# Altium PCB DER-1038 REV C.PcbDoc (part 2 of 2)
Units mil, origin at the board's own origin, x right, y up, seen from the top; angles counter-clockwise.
Board outline 9818.9 x 992.13 mil, 2 copper layers (TOP, BOTTOM), stack 10.4 mil thick; 94 components, 52 nets, 258 pads, 996 vias.

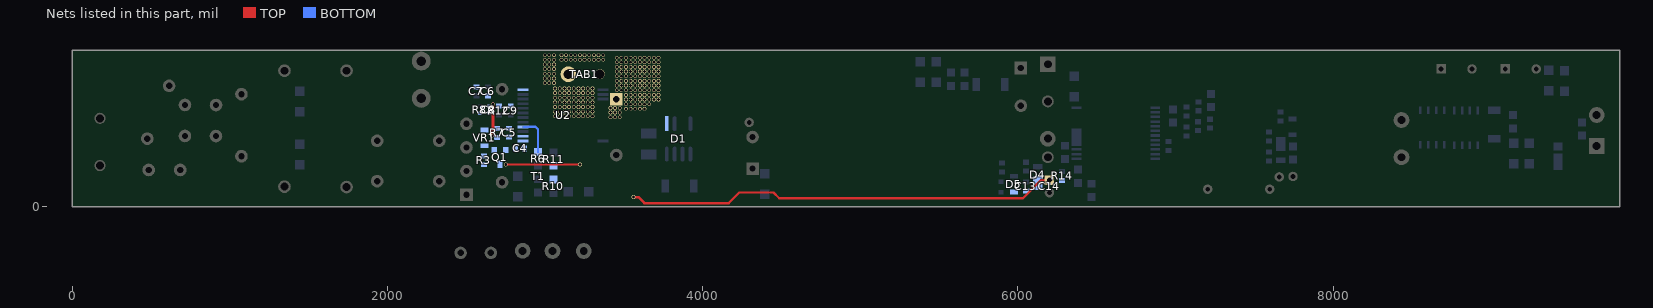
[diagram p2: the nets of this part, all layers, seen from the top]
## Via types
v1: diameter 24, hole 18, TOP to BOTTOM, 995 vias
v2: diameter 60, hole 35, TOP to BOTTOM, 1 vias

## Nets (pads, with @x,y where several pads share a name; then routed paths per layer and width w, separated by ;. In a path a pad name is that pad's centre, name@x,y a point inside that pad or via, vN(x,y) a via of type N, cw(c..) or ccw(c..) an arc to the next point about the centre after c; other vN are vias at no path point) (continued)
N13967788: C5.1 R6.2 R7.1 U2.4 | length 247.7
  BOTTOM w15: U2.4@2860.26,506.18 2892.32,506.18 2893.5,507.36 2902.79,507.36 2903.59,508.15 2937.85,508.15 2955,491 R6.2@2955,346
N13967796: R10.2 R11.2
N13967854: C4.1 Q1.2 U2.1
N13967858: C4.2 C5.2 C6.2 C7.2 C8.2 C9.2 R7.2 R12.1 U2.2 U2.12 VR1.2 | length 205.7
  TOP w20: v1(2661,448) 2661,477 2670,486 v1(2670,650)
N13968000: C8.1 R8.2
N13968020: Q1.1 R3.2 VR1.1
N13971397: D1.1 T1.1 TAB1.1 TAB1.2 U2.16
  other v1: 3414.28,567.95 3443.81,567.95 3473.34,567.95 3063.23,573.58 3093.23,573.58 3122.76,573.58 3152.28,573.58 3181.81,573.58 3211.34,573.58 3240.87,573.58 3270.39,573.58 3299.92,573.58 3414.28,597.47 3443.81,597.47 3473.34,597.47 3063.23,603.11 3093.23,603.11 3122.76,603.11 3152.28,603.11 3181.81,603.11 3211.34,603.11 3240.87,603.11 3270.39,603.11 3299.92,603.11 3513.28,620.95 3542.81,620.95 3572.34,620.95 3601.87,620.95 3631.39,620.95 3414.28,627 3443.81,627 3473.34,627 3063.23,632.64 3093.23,632.64 3122.76,632.64 3152.28,632.64 3181.81,632.64 3211.34,632.64 3240.87,632.64 3270.39,632.64 3299.92,632.64 3513.28,650.47 3542.81,650.47 3572.34,650.47 3601.87,650.47 3631.39,650.47 3660.92,650.47 3063.23,662.16 3093.23,662.16 3122.76,662.16 3152.28,662.16 3181.81,662.16 3211.34,662.16 3240.87,662.16 3270.39,662.16 3299.92,662.16 3513.28,680 3542.81,680 3572.34,680 3601.87,680 3631.39,680 3660.92,680 3690.45,680 3719.98,680 3063.23,691.69 3093.23,691.69 3122.76,691.69 3152.28,691.69 3181.81,691.69 3211.34,691.69 3240.87,691.69 3270.39,691.69 3299.92,691.69 3513.28,709.53 3542.81,709.53 3572.34,709.53 3601.87,709.53 3631.39,709.53 3660.92,709.53 3690.45,709.53 3719.98,709.53 3063.23,721.22 3093.23,721.22 3122.76,721.22 3152.28,721.22 3181.81,721.22 3211.34,721.22 3240.87,721.22 3270.39,721.22 3299.92,721.22 3454.23,739.05 3483.76,739.05 3513.28,739.05 3542.81,739.05 3572.34,739.05 3601.87,739.05 3631.39,739.05 3660.92,739.05 3690.45,739.05 3719.98,739.05 3063.23,750.75 3093.23,750.75 3122.76,750.75 3152.28,750.75 3181.81,750.75 3211.34,750.75 3240.87,750.75 3270.39,750.75 3299.92,750.75 3454.23,768.58 3483.76,768.58 3513.28,768.58 3542.81,768.58 3572.34,768.58 3601.87,768.58 3631.39,768.58 3660.92,768.58 3690.45,768.58 3719.98,768.58 2997.23,784.58 3026.76,784.58 3056.28,784.58 3454.23,798.11 3483.76,798.11 3513.28,798.11 3542.81,798.11 3572.34,798.11 3601.87,798.11 3631.39,798.11 3660.92,798.11 3690.45,798.11 3719.98,798.11 2997.23,814.11 3026.76,814.11 3056.28,814.11 3454.23,827.64 3483.76,827.64 3513.28,827.64 3542.81,827.64 3572.34,827.64 3601.87,827.64 3631.39,827.64 3660.92,827.64 3690.45,827.64 3719.98,827.64 2997.23,843.64 3026.76,843.64 3056.28,843.64 3454.23,857.16 3483.76,857.16 3513.28,857.16 3542.81,857.16 3572.34,857.16 3601.87,857.16 3631.39,857.16 3660.92,857.16 3690.45,857.16 3719.98,857.16 2997.23,873.16 3026.76,873.16 3056.28,873.16 3454.23,886.69 3483.76,886.69 3513.28,886.69 3542.81,886.69 3572.34,886.69 3601.87,886.69 3631.39,886.69 3660.92,886.69 3690.45,886.69 3719.98,886.69 2997.23,902.69 3026.76,902.69 3056.28,902.69 3454.23,916.22 3483.76,916.22 3513.28,916.22 3542.81,916.22 3572.34,916.22 3601.87,916.22 3631.39,916.22 3660.92,916.22 3690.45,916.22 3719.98,916.22 2997.23,932.22 3026.76,932.22 3056.28,932.22 3103.23,932.22 3132.76,932.22 3162.28,932.22 3191.81,932.22 3221.34,932.22 3250.87,932.22 3280.39,932.22 3309.92,932.22 3339.45,932.22 3368.98,932.22 3454.23,945.75 3483.76,945.75 3513.28,945.75 3542.81,945.75 3572.34,945.75 3601.87,945.75 3631.39,945.75 3660.92,945.75 3690.45,945.75 3719.98,945.75 2997.23,961.75 3026.76,961.75 3056.28,961.75 3103.23,961.75 3132.76,961.75 3162.28,961.75 3191.81,961.75 3221.34,961.75 3250.87,961.75 3280.39,961.75 3309.92,961.75 3339.45,961.75 3368.98,961.75
VCCP: C13.1 C14.1 D4.1 D5.2 Q1.3 R3.1 R14.1 | length 3216.4
  TOP w15: v1(2750,268) v1(3221,268) ; v1(3561,61) 3592,61 3630,23 4165,23 4232,90 4450,90 4486,54 6032,54 6147,169 C14.1@6200.37,169
pads on no net: D1. PI_SPARK_GAP_6P4MM.1 PI_SPARK_GAP_6P4MM.2 T1.2 T1.3 T2.2 T2.4 T2.8 U1.6 U2.7 U2.9 U2.10 U2.11 U2.13 U2.14 U2.15 U3.8 U3.9 U3.10 U3.11 U3.12

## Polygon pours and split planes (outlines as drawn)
N13421894 on BOTTOM "BOTTOM-N13421894" (solid, remove dead copper, pour order 10): 19 vertices, not listed, extent 6937,341 7032.5,406
N13967702 on BOTTOM "BOTTOM-N13967702" (solid, remove dead copper, pour order 44): 3033,120 3103,120 3111,128 3174,128 3177,125 3177,59 3047,59 3031,59 3030,60 3030,67 3028,69 3028,115
N13420648 on BOTTOM "BOTTOM-N13420648" (solid, remove dead copper, pour order 59): 22 vertices, not listed, extent 3335,386 3707,497
N13420648 on BOTTOM "BOTTOM-N13420648 1" (solid, remove dead copper, pour order 39): 2440,564 2515,564 2539,540 2539,495 2530,486 2458,486 2429,515 2429,553
N13967734 on BOTTOM "BOTTOM-N13967734" (solid, remove dead copper, pour order 5): 2618,745 2618,794 2624,800 2648,800 2656,792 2656,745
N13515268 on BOTTOM "BOTTOM-N13515268" (solid, remove dead copper, pour order 11): 6037,237 6037,146 6041,142 6068,142 6072,146 6072,235 6067,240 6040,240
N13473411 on BOTTOM "BOTTOM-N13473411" (solid, remove dead copper, pour order 14): 5877,234 5877,149 5880,146 5910,146 5918,154 5918,230 5911,237 5880,237
N13967764 on BOTTOM "BOTTOM-N13967764" (solid, remove dead copper, pour order 0): 2804,544 2888,544 2890,542 2890,528 2889,527 2805,527 2799,533 2799,539
N13968020 on BOTTOM "BOTTOM-N13968020" (solid, remove dead copper, pour order 43): 2586,400 2586,313 2592,307 2659,307 2693,341 2693,379 2671,401 2621,401 2620,402 2588,402
BPS on BOTTOM "BOTTOM-BPS" (solid, remove dead copper, pour order 30): 6845,548 6949,548 6960,559 7014,559 7020,553 7020,480 7014,474 6995,474 6959,510 6959,525 6951,533 6846,533 6842,537 6842,545
N13967710 on BOTTOM "BOTTOM-N13967710" (solid, remove dead copper, pour order 22): 2691,598 2800,598 2803,595 2803,577 2806,574 2806,558 2696,558 2687,567 2687,594
N13421012 on BOTTOM "BOTTOM-N13421012" (solid, remove dead copper, pour order 8): 17 vertices, not listed, extent 6843,557 7047,578
N13925956 on BOTTOM "BOTTOM-N13925956" (solid, remove dead copper, pour order 73): 17 vertices, not listed, extent 435,191 744,544
N13967854 on BOTTOM "BOTTOM-N13967854" (solid, remove dead copper, pour order 46): 23 vertices, not listed, extent 2734,304 2896,426
N13523865 on BOTTOM "BOTTOM-N13523865" (solid, remove dead copper, pour order 27): 17 vertices, not listed, extent 6342,211 6407,312
N13420648 on BOTTOM "BOTTOM-N13420648 2" (solid, remove dead copper, pour order 31): 2687,759 2687,707 2697,697 2754,697 2766,709 2766,781 2761,786 2714,786
N13422446 on BOTTOM "BOTTOM-N13422446" (solid, remove dead copper, pour order 7): 8693,665 8693,589 8696,586 8718,586 8719,587 8719,654 8718.5,654.5 8718.5,666.5 8716,669 8708,669 8697,669
N13967858 on BOTTOM "BOTTOM-N13967858" (solid, remove dead copper, pour order 58): 35 vertices, not listed, extent 2544,622 2893,777
N13440082 on BOTTOM "BOTTOM-N13440082" (solid, remove dead copper, pour order 25): 7648,556 7648,527 7647,526 7648,525 7770,525 7770,567 7764,573 7714,573 7702,561 7653,561
VCCP on BOTTOM "BOTTOM-VCCP" (solid, remove dead copper, pour order 35): 2591,284 2591,249 2596,244 2743,244 2758,259 2758,277 2752,283 2739,296 2695,296 2682,283 2592,283
VCCP on BOTTOM "BOTTOM-VCCP 1" (solid, remove dead copper, pour order 60): 26 vertices, not listed, extent 5949,78 6300,198
N13925782 on BOTTOM "BOTTOM-N13925782" (solid, remove dead copper, pour order 84): 21 vertices, not listed, extent 876,26 1534,492
N13967710 on BOTTOM "BOTTOM-N13967710 1" (solid, remove dead copper, pour order 18): 3021.5,320.5 3026,316 3079,316 3081,318 3081,368 3057,392 3023,392 3017.5,386.5 3017.5,383.5 3021.5,379.5
N13523772 on BOTTOM "BOTTOM-N13523772" (solid, remove dead copper, pour order 37): 6484,177 6492,169 6492,123 6491,122 6421,122 6366,122 6362,126 6358,130 6358,147 6358,177
N13420620 on BOTTOM "BOTTOM-N13420620" (solid, remove dead copper, pour order 80): 21 vertices, not listed, extent 5334,799 6406,990
N13925608 on BOTTOM "BOTTOM-N13925608" (solid, remove dead copper, pour order 42): 2289,187 2289,109 2300,98 2371,98 2379,106 2379,184 2360,203 2319,203 2305,203
N13420656 on BOTTOM "BOTTOM-N13420656" (solid, remove dead copper, pour order 29): 9061,913 9140,913 9142,911 9142,864 9122,844 9062,844 9058,848 9058,910
VCCP on BOTTOM "BOTTOM-VCCP 2" (solid, remove dead copper, pour order 56): 3208,285 3304,285 3495,94 3546,94 3573,67 3573,53 3568,48 3496,48 3288,256 3214,256 3206,264 3206,283
N13971397 on BOTTOM "BOTTOM-N13971397" (solid, remove dead copper, pour order 93): 39 vertices, not listed, extent 2968,353 4085,986
no net on BOTTOM "BOTTOM-No Net" (solid, remove dead copper, pour order 90): 108 vertices, not listed, extent 6842,554.5 9518,986
N13420656 on BOTTOM "BOTTOM-N13420656 1" (solid, remove dead copper, pour order 65): 9582.5,309.5 9593,299 9710,299 9722,311 9722,355 9722,474 9720,476 9717,479 9619,479 9561,479 9557,475 9557,423 9582.5,397.5
N13925608 on BOTTOM "BOTTOM-N13925608 1" (solid, remove dead copper, pour order 38): 2523,339 2465,339 2449,355 2449,391 2449,423 2452,426 2463,426 2518,426 2541,403 2541,357
N13911889 on BOTTOM "BOTTOM-N13911889" (solid, remove dead copper, pour order 61): 19 vertices, not listed, extent 5335,761 5688,878
N13925908 on BOTTOM "BOTTOM-N13925908" (solid, remove dead copper, pour order 66): 1468,521 1436,521 1403,521 1384,540 1301,540 1188,540 1188,628 1196,636 1459,636 1476,636 1480,632 1480,531 1470,521
N13967764 on BOTTOM "BOTTOM-N13967764 1" (solid, remove dead copper, pour order 19): 2563,624 2596,624 2596,671 2585,682 2585,702 2585,718 2582,721 2546,721 2546,634 2556,624
N13422446 on BOTTOM "BOTTOM-N13422446 1" (solid, remove dead copper, pour order 4): 8906,660 8906,590 8911,585 8928,585 8931,588 8931,658 8924,665 8911,665
N13515819 on BOTTOM "BOTTOM-N13515819" (solid, remove dead copper, pour order 15): 7575,433 7575,335 7578,332 7612,332 7614,334 7614,428 7609,433
N13423706 on BOTTOM "BOTTOM-N13423706" (solid, remove dead copper, pour order 9): 18 vertices, not listed, extent 5877,79 5988,150
N13421894 on BOTTOM "BOTTOM-N13421894 1" (solid, remove dead copper, pour order 91): 27 vertices, not listed, extent 8375,61 9462.5,541
N13420620 on BOTTOM "BOTTOM-N13420620 1" (solid, remove dead copper, pour order 53): 3249,46 3253,42 3289,6 3290,5 3387,5 3396,14 3396,36 3340,92 3331,101 3331,102 3305,128 3249,128
N13967734 on BOTTOM "BOTTOM-N13967734 1" (solid, remove dead copper, pour order 1): 2828,632 2895,632 2900,637 2919,637 2923,633 2923,618 2916,611 2901,611 2896,616 2828,616 2826,618 2826,630
BPS on BOTTOM "BOTTOM-BPS 1" (solid, remove dead copper, pour order 20): 7622.65,573.35 7634.3,585 7685,585 7686,586 7686,616 7683,619 7585.93,619 7573.3,606.37 7572,605.07 7572,586 7584.65,573.35
N13925722 on BOTTOM "BOTTOM-N13925722" (solid, remove dead copper, pour order 87): 36 vertices, not listed, extent 1611,59 2287,987
N13912909 on BOTTOM "BOTTOM-N13912909" (solid, remove dead copper, pour order 69): 22 vertices, not listed, extent 5884,621 6403,820
N13967858 on BOTTOM "BOTTOM-N13967858 1" (solid, remove dead copper, pour order 52): 29 vertices, not listed, extent 2590,352 2870,505
N13423706 on BOTTOM "BOTTOM-N13423706 1" (solid, remove dead copper, pour order 47): 20 vertices, not listed, extent 6201,207 6402,341
N13967788 on BOTTOM "BOTTOM-N13967788" (solid, remove dead copper, pour order 17): 2924,385 2924,323 2929,318 2980,318 2981,319 2981,378 2963,396 2949,396 2948,397 2936,397
N13968000 on BOTTOM "BOTTOM-N13968000" (solid, remove dead copper, pour order 6): 2574,607 2651,607 2652,606 2652,581 2651,580 2576,580 2573,583 2573,606
N13911953 on BOTTOM "BOTTOM-N13911953" (solid, remove dead copper, pour order 55): 5716,723 5628,723 5569,723 5550.5,741.5 5550.5,791 5611,791 5681,791 5689,791 5713,815 5754,815 5754,744 5733,723
N13925960 on BOTTOM "BOTTOM-N13925960" (solid, remove dead copper, pour order 78): 18 vertices, not listed, extent 118,523 751,809
no net on BOTTOM "BOTTOM-No Net 1" (solid, remove dead copper, pour order 75): 29 vertices, not listed, extent 7012,162 7835,881
N13422446 on BOTTOM "BOTTOM-N13422446 2" (solid, remove dead copper, pour order 2): 6843,519 6923,519 6925,521 6940,521 6944.5,516.5 6944.5,507.5 6944.5,500.5 6940,496 6935,496 6923,496 6916,503 6843,503 6842,504 6842,518
N13423710 on BOTTOM "BOTTOM-N13423710" (solid, remove dead copper, pour order 49): 17 vertices, not listed, extent 7576,164 7692,311
N13423714 on BOTTOM "BOTTOM-N13423714" (solid, remove dead copper, pour order 63): 7636,338 7636,446 7623,459 7583,459 7577,465 7577,486 7678,486 7755,486 7769,472 7769,359 7768,358 7716,358 7691,333 7689,331 7643,331
N13513324 on BOTTOM "BOTTOM-N13513324" (solid, remove dead copper, pour order 24): 6842,622 6842,687 6863,708 6892,708 6903,697 6903,621 6843,621
N13967468 on BOTTOM "BOTTOM-N13967468" (solid, remove dead copper, pour order 71): 19 vertices, not listed, extent 2461,3 2858,189.5
N13967734 on BOTTOM "BOTTOM-N13967734 2" (solid, remove dead copper, pour order 3): 2827,486 2899,486 2902,489 2918,489 2921,486 2921,468 2918,465 2897,465 2894,468 2827,468 2826,469 2826,485
N13967796 on BOTTOM "BOTTOM-N13967796" (solid, remove dead copper, pour order 34): 3027,285 3027,150 3028,149 3078,149 3078,283 3076,285
N13421042 on BOTTOM "BOTTOM-N13421042" (solid, remove dead copper, pour order 13): 7125,467 7125,497 7127,499 7163,499 7168,504 7182,504 7187,509 7194,516 7237,516 7239,514 7239,509 7239,483 7214,483 7179,483 7163,467
N13420648 on BOTTOM "BOTTOM-N13420648 3" (solid, remove dead copper, pour order 57): 7259,133 7259,12 7250,3 7113,3 7106,10 7106,51 7188,133
N13420648 on BOTTOM "BOTTOM-N13420648 4" (solid, remove dead copper, pour order 96): 54 vertices, not listed, extent 4172,4 6484,975
N13449363 on BOTTOM "BOTTOM-N13449363" (solid, remove dead copper, pour order 51): 22 vertices, not listed, extent 6036,232 6227,350
N13513324 on BOTTOM "BOTTOM-N13513324 1" (solid, remove dead copper, pour order 76): 33 vertices, not listed, extent 9243.5,509 9736,768
N13420656 on BOTTOM "BOTTOM-N13420656 2" (solid, remove dead copper, pour order 79): 35 vertices, not listed, extent 7583,77 8716.5,906
N13926028 on BOTTOM "BOTTOM-N13926028" (solid, remove dead copper, pour order 68): 130,302 130,206 154,182 515,182 526,193 526,262 510,278 255,278 223,310 217,316 144,316
N13523750 on BOTTOM "BOTTOM-N13523750" (solid, remove dead copper, pour order 26): 4364,106 4364,29 4378,15 4412,15 4422,25 4422,99 4414,107 4365,107
N13967468 on BOTTOM "BOTTOM-N13967468 1" (solid, remove dead copper, pour order 70): 3414,340 3414,274 3557,131 3585,131 3639,77 3676,77 3769,77 3786,94 3786,170 3771,185 3654,185 3478,361 3435,361
N13925794 on BOTTOM "BOTTOM-N13925794" (solid, remove dead copper, pour order 83): 25 vertices, not listed, extent 872,597 1544,948
N13925904 on BOTTOM "BOTTOM-N13925904" (solid, remove dead copper, pour order 64): 1338,435 1437,435 1465,435 1476,424 1476,367 1453,344 1321,344 1320.5,343.5 1182,343.5 1182,420 1182,430 1185,433 1331,433 1336,433
N13421012 on BOTTOM "BOTTOM-N13421012 1" (solid, remove dead copper, pour order 50): 22 vertices, not listed, extent 7036,489 7165,626
N13473415 on BOTTOM "BOTTOM-N13473415" (solid, remove dead copper, pour order 36): 5883,292 5969,292 5998,263 5998,185 5993,180 5953,180 5950,183 5950,249 5938,261 5885,261 5880,266 5880,289
N13967780 on BOTTOM "BOTTOM-N13967780" (solid, remove dead copper, pour order 33): 2930,287 2978,287 2979,286 2979,150 2978,149 2931,149 2930,150
N13420620 on BOTTOM "BOTTOM-N13420620 2" (solid, remove dead copper, pour order 82): 26 vertices, not listed, extent 3609,46 4433,382
N13420656 on BOTTOM "BOTTOM-N13420656 3" (solid, remove dead copper, pour order 67): 51 vertices, not listed, extent 6842,432 7388,825
N13925544 on BOTTOM "BOTTOM-N13925544" (solid, remove dead copper, pour order 77): 30 vertices, not listed, extent 2136,181 2537,769
N13523750 on BOTTOM "BOTTOM-N13523750 1" (solid, remove dead copper, pour order 23): 6399,51 6399,20 6405,14 6427,14 6450,37 6490,37 6491,38 6491,84 6489,86 6461,86 6460,87 6435,87
N13916087 on BOTTOM "BOTTOM-N13916087" (solid, remove dead copper, pour order 12): 6844,459 6943,459 6974,428 6974,396 6935.5,396 6935.5,427.5 6919,444 6845,444 6842,447 6842,457
N13967706 on BOTTOM "BOTTOM-N13967706" (solid, remove dead copper, pour order 45): 2798,226 2798,162 2806,154 2851,154 2920,85 2920,62 2979,62 2980,63 2980,113 2976,117 2916,117 2865,168 2865,217 2854,228 2800,228
N13925608 on BOTTOM "BOTTOM-N13925608 2" (solid, remove dead copper, pour order 62): 1626,892 1626,832 1665,793 1667,793 1775,793 1788,806 1788,912 1776,924 1658,924
N13967788 on BOTTOM "BOTTOM-N13967788 1" (solid, remove dead copper, pour order 28): 2679,515 2894,515 2894,498 2799,498 2787,486 2787,482 2678,482 2676,484 2676,512
N13925608 on BOTTOM "BOTTOM-N13925608 3" (solid, remove dead copper, pour order 41): 2331,469 2364,469 2375,458 2375,391 2355,371 2303,371 2285,389 2285,422 2285.5,422.5 2285.5,459.5 2295,469
N13421702 on BOTTOM "BOTTOM-N13421702" (solid, remove dead copper, pour order 72): 9439,444 9439,355 9136,355 9106,355 9098,363 9098,521 9099,522 9361,522 9402,522 9439,485
VCCP on TOP "TOP-VCCP" (solid, remove dead copper, pour order 21): 6163,195 6225,195 6226,194 6226,143 6145,143 6139.5,148.5 6139.5,179.5 6153,193 6155,195
N13420648 on TOP "TOP-N13420648" (solid, remove dead copper, pour order 95): 47 vertices, not listed, extent 4544,86.5 6499,806
N13420656 on TOP "TOP-N13420656" (solid, remove dead copper, pour order 81): 29 vertices, not listed, extent 8654,330 9722,990
N13420620 on TOP "TOP-N13420620" (solid, remove dead copper, pour order 88): 25 vertices, not listed, extent 4256,200 6238,974
N13420648 on TOP "TOP-N13420648 1" (solid, remove dead copper, pour order 94): 56 vertices, not listed, extent 2429,111 4354.5,984
GND on TOP "TOP-GND" (solid, remove dead copper, pour order 16): 8857,904 8905,904 8918,891 8918,852 8910,844 8850,844 8844,850 8844,891
N13925544 on TOP "TOP-N13925544" (solid, remove dead copper, pour order 48): 2459,255 2459,194 2471,182 2557,182 2574,199 2574,271 2569,276 2480,276
N13912909 on TOP "TOP-N13912909" (solid, remove dead copper, pour order 40): 6150,728 6150,658 6172,636 6214,636 6231,653 6231,727 6214,744 6166,744
N13925608 on TOP "TOP-N13925608" (solid, remove dead copper, pour order 85): 31 vertices, not listed, extent 1693,24 2535,915
N13421894 on TOP "TOP-N13421894" (solid, remove dead copper, pour order 92): 23 vertices, not listed, extent 8373,22 9464,542
N13971397 on TOP "TOP-N13971397" (solid, remove dead copper, pour order 89): 17 vertices, not listed, extent 2965,547.5 3776,984
N13967468 on TOP "TOP-N13967468" (solid, remove dead copper, pour order 86): 17 vertices, not listed, extent 2459,6 3500,359.5
N13420656 on TOP "TOP-N13420656 1" (solid, remove dead copper, pour order 54): 8451,498 8387,498 8340,545 8340,597 8349,606 8451,606 8474,606 8487,593 8487,570 8487,534
GND on TOP "TOP-GND 1" (solid, remove dead copper, pour order 32): 9255,902 9255,866 9281,840 9328,840 9354,866 9354,904 9342,916 9269,916
N13420648 on TOP "TOP-N13420648 2" (solid, remove dead copper, pour order 74): 22 vertices, not listed, extent 6172,4 7237,144.75

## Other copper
BOTTOM:
  region net N13925722: 2189,853.31 2217,853.31 2217,836.31 2204.69,816.96 cw(c2203,818.03) 2201.31,816.96 2189,836.31
  region net N13925782: 1529.69,67 1529.69,95 1546.69,95 1566.04,82.69 cw(c1564.97,81) 1566.04,79.31 1546.69,67
  region net N13925722: 1620,95 1620,67 1603,67 1583.65,79.31 cw(c1584.73,81) 1583.65,82.69 1603,95
  region net N13925722: 2217,853.31 2245,853.31 2245,836.31 2232.69,816.96 cw(c2231,818.03) 2229.31,816.96 2217,836.31
  region net N13925782: 1529.69,95 1529.69,123 1546.69,123 1566.04,110.69 cw(c1564.97,109) 1566.04,107.31 1546.69,95
  region net N13925722: 1620,123 1620,95 1603,95 1583.65,107.31 cw(c1584.73,109) 1583.65,110.69 1603,123
  region net GND: 9285,906 9286,906 9287,907 9287,910 9251,946 9251,977 9257,983 9509,983 9518,974 9518,835 9515,832 9295,832 9221,758 8937,758 8887,808 8887,837 8884,840 8880,840 8877,837 8877,806 8935,748 9161,748 9192,717 9192,568 9179,555 9095,555 9094.5,554.5 8982.5,554.5 8958,579 8958,661 8939.5,679.5 8897.5,679.5 8877,659 8877,582 8746,582 8744,584 8744,674 8731.5,686.5 8684.5,686.5 8668,670 8668,589 8662,583 8533,583 8528,588 8528,768 8571,811 8748,811 8768,831 8768,893 8779,904 8973,904 9019,858 9019,838 9036.5,820.5 9137.5,820.5 9220,903 9238,903 9255,886 9257.18,886 ccw(c9257.18,888) 9258.59,889.41 9207.01,941 8459,941 8421,903 7144,903 7018,777 7018,685 7035,668 7093,668 7166.5,741.5 7247.5,741.5 7249,740 7249,690 7247,688 7201,688 7163,650 7127,650 7091,614 7033,614 7011,592 6844,592 6842,594 6842,607 6912,607 6947,642 6947,834 7099,986 9205,986
  region net N13925544: 2217,763 2189,763 2189,780 2201.31,799.35 cw(c2203,798.27) 2204.69,799.35 2217,780
  region net N13925794: 1540.69,864 1540.69,892 1557.69,892 1577.04,879.69 cw(c1575.97,878) 1577.04,876.31 1557.69,864
  region net GND: 7733,162 7718,177 7718,274 7721,277 7721,322 7724,325 7769,325 7775,319 7775,259.83 ccw(c7777,259.83) 7778.41,258.41 7803,283 7803,787 7740,850 7207,850 7080,723 7080,702 7028,650 7012,666 7012,710 7183,881 7775,881 7835,821 7835,206 7791,162
  region net N13925544: 2245,763 2217,763 2217,780 2229.31,799.35 cw(c2231,798.27) 2232.69,799.35 2245,780
  region net N13925794: 1540.69,836 1540.69,864 1557.69,864 1577.04,851.69 cw(c1575.97,850) 1577.04,848.31 1557.69,836
  region net N13925608: 1631,864 1631,836 1614,836 1594.65,848.31 cw(c1595.73,850) 1594.65,851.69 1614,864
  region net N13925608: 1631,892 1631,864 1614,864 1594.65,876.31 cw(c1595.73,878) 1594.65,879.69 1614,892

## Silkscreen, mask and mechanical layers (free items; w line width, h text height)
Top Overlay:
  drawing of 383 lines, arcs and shapes, not listed
  text "24V" at 9555,919 h40
  text "4.167A" at 9548,861 h40
  text "-Vo" at 9698,737 h40
  text "N" at 219,733 h40
  text "+" at 6278,228 h75 r270
  text "+Vo" at 9696,224 h40
  text "DER-1038" at 8201,166 h25
  text "REV C" at 8202,122 h25
  text "2420" at 8201,83 h25
  text "L" at 165,51 h40
  text "S/N" at 8202,37 h25
Bottom Solder:
  region: 3318.5,755.5 3298,776 3033,776 3030,779 3030,908 3030,937 3057,964 3728,964 3739,953 3739,672 3671,604 3614,547 3407,547 3405,549 3405,643 3404.5,643.5 3404.5,749.5 3398.5,755.5
  region: 1528.45,897.35 1528.45,832.35 1534.45,826.35 1639.45,826.35 1640.45,827.35 1640.45,896.35 1639.45,897.35
  region: 1515.29,133.05 1515.29,68.05 1521.29,62.05 1626.29,62.05 1627.29,63.05 1627.29,132.05 1626.29,133.05
  region: 8874,905 8949,905 9041,813 9181,813 9272,904 9311,904 9329,886 9329,849 9317,837 9288,837 9212,761 8970,761 8885,846 8867,846 8844,846 8827,863 8827,897 8836,906 8873,906
  region: 8400,520 8400,808 8498,906 8713,906 8718,901 8718,845 8645,845 8641,849 8528,849 8477,798 8477,528 8466,517 8403,517
  region: 5599,659 6003,659 6116,546 6329,546 6335,540 6335,429 6334,428 6272,428 6263,419 6243,399 6170,399 6131.5,360.5 6129.5,360.5 6102,333 5873,333 5832,292 5832,34 5627,34 5592,69 5592,652
  region: 8488,177 8488,85 8502,71 9070,71 9080,81 9080,304 9011,373 8502,373 8404,373 8386,355 8386,279
  region: 2187,839 2187,770 2189,768 2247,768 2247,842 2190,842
OUTLINE:
  lines w1: -464,-5387 -464,-3587 7336,-3587 ; -464,-3887 3136,-3887 ; 1036,-5387 1036,-3587 ; 1036,-5037 3136,-5037 ; 1036,-4787 3136,-4787 ; 1036,-4487 3136,-4487 ; 1036,-4187 3136,-4187 ; 2336,-4787 2336,-4762 2336,-3587 ; 2336,3813 2336,4113 2336,5013 ; 2336,4413 7336,4413 ; 2336,4713 7336,4713 ; 2736,3813 2736,4113 2736,4713 ; 3136,-5387 3136,-3587 ; 3136,-5087 5636,-5087 ; 3136,-4687 7336,-4687 ; 3136,-4087 7336,-4087 ; 3636,-5087 3636,-4687 ; 4036,-5387 4036,-5087 ; 4836,-5087 4836,-4687 ; 5436,3813 5436,4113 ; 5436,4013 5436,4413 5436,4713 ; 5636,-5387 5636,-5087 ; 6336,3813 6336,4113 6336,4413 6336,4713 ; 7336,-5087 5636,-5087 ; -9164,-5687 7836,-5687 7836,5313 -9164,5313 -9164,-5687 ; -8664,-5387 7336,-5387 7336,3813 7336,5013 -8564,5013 -8664,5013 -8664,-5387 ; 0,0 9818.9,0 9818.9,992.13 0,992.13 0,0
  text "REVISIONS" at 4486,4813 h100
  text "REV" at 2386,4513 h100
  text "DESCRIPTION" at 3436,4513 h100
  text "DATE" at 5686,4513 h100
  text "APPROVED" at 6436,4513 h100
  text "UNLESS OTHERWISE SPECIFIED" at -389,-3762 h40
  text "SIGNATURES" at 1461,-3762 h50
  text "DATE" at 2586,-3762 h50
  text "COMPANY NAME AND ADDRESS" at 3836,-3887 h100
  text "DIMENSIONS ARE IN INCHES" at -389,-4037 h40
  text "TOLERANCES ON:" at -389,-4212 h40
  text "2 PL DECIMALS +" at -389,-4362 h40
  text "3 PL DECIMALS +" at -389,-4512 h40
  text "ANGLES +" at -389,-4662 h40
  text "FRACTIONS +" at -389,-4812 h40
  text "SIZE" at 3186,-4837 h100
  text "FSCM NO" at 3736,-4837 h100
  text "DWG NO" at 4936,-4837 h100
  text "SCALE" at 3186,-5237 h100
  text "SHEET" at 5736,-5237 h100
DIMENSION:
  lines w1: 0,1230 4372,1230 0,1230 ; 0,1230 150,1205 ; 0,1230 150,1255 ; 0,1230 150,1205 ; 0,1230 150,1255 ; 150,1205 150,1255 ; 150,1205 150,1255 ; 4417,1140 4417,1200 ; 4417,1140 4442,1140 4417,1140 ; 4417,1140 4417,1200 ; 4417,1200 4442,1200 4417,1200 ; 4831,1140 4831,1200 ; 4831,1140 4806,1140 4831,1140 ; 4831,1140 4831,1200 ; 4831,1200 4806,1200 4831,1200 ; 9668.9,1205 9668.9,1255 ; 9668.9,1205 9818.9,1230 ; 9668.9,1205 9668.9,1255 ; 9668.9,1205 9818.9,1230 ; 9668.9,1255 9818.9,1230 ; 9668.9,1255 9818.9,1230 ; 9818.9,1230 4876,1230 9818.9,1230 ; 9906,429 9906,489 ; 9906,429 9931,429 9906,429 ; 9906,429 9906,489 ; 9906,489 9931,489 9906,489 ; 10055,150 10105,150 ; 10055,150 10080,0 ; 10055,150 10105,150 ; 10055,150 10080,0 ; 10055,842.13 10105,842.13 ; 10055,842.13 10080,992.13 ; 10055,842.13 10105,842.13 ; 10055,842.13 10080,992.13 ; 10080,0 10105,150 ; 10080,0 10105,150 ; 10080,0 10080,383.5 10080,0 ; 10080,992.13 10105,842.13 ; 10080,992.13 10105,842.13 ; 10080,992.13 10080,654.5 10080,992.13 ; 10254,429 10254,489 ; 10254,429 10229,429 10254,429 ; 10254,429 10254,489 ; 10254,489 10229,489 10254,489 ; 0,1092.13 0,1330 0,1092.13 ; 9818.9,1092.13 9818.9,1330 9818.9,1092.13 ; 9918.9,0 10180,0 9918.9,0 ; 9918.9,992.13 10180,992.13 9918.9,992.13
  text "9.82" at 4499.75,1260 h60
  text "9.82" at 4499.75,1260 h60
  text "249.4" at 4467,1140 h60
  text "249.4" at 4467,1140 h60
  text ".99" at 9988.75,549 h60
  text ".99" at 9988.75,549 h60
  text "25.2" at 9956,429 h60
  text "25.2" at 9956,429 h60
NCLEGEND-1-2:
  circle w1: c11143,1234 r15
  circle w1: c11143,634 r20
  circle w1: c11143,274 r25
  circle w1: c11143,874 r20
  circle w1: c11143,1354 r6
  circle w1: c11143,-86 r30
  circle w1: c11143,34 r30
  circle w1: c11143,394 r25
  lines w1: 10904,-26 14614,-26 ; 10904,94 14614,94 ; 10904,214 14614,214 ; 10904,334 14614,334 ; 10904,454 14614,454 ; 10904,574 14614,574 ; 10904,694 14614,694 ; 10904,814 14614,814 ; 10904,934 14614,934 ; 10904,1054 14614,1054 ; 10904,1174 14614,1174 ; 10904,1294 14614,1294 ; 10904,1414 14614,1414 ; 10904,1534 14614,1534 ; 10904,1654 14614,1654 ; 11382,-146 11382,1534 ; 12454,-146 12454,1534 ; 13526,-146 13526,1534 ; 14202,-146 14202,1534 ; 10904,-146 10904,1904 14614,1904 14614,-146 10904,-146 ; 11123,134 11143,174 11163,134 11123,134 ; 11123,974 11163,974 11163,1014 11123,1014 11123,974 ; 11128,1114 11143,1129 11158,1114 11143,1099 11128,1114 ; 11138,484 ccw(c11138,514) 11138,544 11148,544 ccw(c11148,514) 11148,484 11138,484 ; 11138,724 ccw(c11138,754) 11138,784 11148,784 ccw(c11148,754) 11148,724 11138,724
  text "DRILL CHART: TOP to BOTTOM" at 12135,1814 h60
  text "ALL UNITS ARE IN MILS" at 12255,1564 h60
  text "FIGURE" at 10999,1444 h60
  text "FINISHED_SIZE" at 11606,1444 h60
  text "TOLERANCE_DRILL" at 12630,1444 h60
  text "PLATED" at 13720,1444 h60
  text "QTY" at 14336,1444 h60
  text "18.0" at 11822,1324 h60
  text "+0.0/-0.0" at 12774,1324 h60
  text "PLATED" at 13720,1324 h60
  text "995" at 14336,1324 h60
  text "30.0" at 11822,1204 h60
  text "+0.0/-0.0" at 12774,1204 h60
  text "PLATED" at 13720,1204 h60
  text "9" at 14384,1204 h60
  text "30.0" at 11822,1084 h60
  text "+0.0/-0.0" at 12774,1084 h60
  text "PLATED" at 13720,1084 h60
  text "2" at 14384,1084 h60
  text "35.0" at 11822,964 h60
  text "+0.0/-0.0" at 12774,964 h60
  text "PLATED" at 13720,964 h60
  text "1" at 14384,964 h60
  text "40.0" at 11822,844 h60
  text "+0.0/-0.0" at 12774,844 h60
  text "PLATED" at 13720,844 h60
  text "18" at 14360,844 h60
  text "40.0" at 11822,724 h60
  text "+0.0/-0.0" at 12774,724 h60
  text "PLATED" at 13720,724 h60
  text "2" at 14384,724 h60
  text "40.0" at 11822,604 h60
  text "+3.0/-3.0" at 12774,604 h60
  text "PLATED" at 13720,604 h60
  text "6" at 14384,604 h60
  text "40.0" at 11822,484 h60
  text "+3.0/-3.0" at 12774,484 h60
  text "PLATED" at 13720,484 h60
  text "2" at 14384,484 h60
  text "50.0" at 11822,364 h60
  text "+0.0/-0.0" at 12774,364 h60
  text "PLATED" at 13720,364 h60
  text "2" at 14384,364 h60
  text "50.0" at 11822,244 h60
  text "+0.0/-0.0" at 12774,244 h60
  text "PLATED" at 13720,244 h60
  text "13" at 14360,244 h60
  text "51.0" at 11822,124 h60
  text "+0.0/-0.0" at 12774,124 h60
  text "PLATED" at 13720,124 h60
  text "2" at 14384,124 h60
  text "60.0" at 11822,4 h60
  text "+0.0/-0.0" at 12774,4 h60
  text "PLATED" at 13720,4 h60
  text "3" at 14384,4 h60
  text "60.0" at 11822,-116 h60
  text "+0.0/-0.0" at 12774,-116 h60
  text "PLATED" at 13720,-116 h60
  text "1" at 14384,-116 h60
FAB_NOTES:
  dashed: 2356,-211 2356,-362 3349,-362 3349,-211
  text "NOTES: PLEASE DELETE THESE PINS" at 121,-329 h60
  text "NOTES: UNLESS OTHERWISE SPECIFIED" at 109.7,-548.7 h60
  text "1.  THROUGH HOLES ARE PLATED THROUGH." at 109.7,-748.7 h60
  text "EXCEPTIONS WILL BE NOTED IN DRILL CHART \"NOTE\"." at 409.7,-948.7 h60
  text "2.  MATERIAL: BASE MATERIAL LAMINATED EPOXY" at 109.7,-1148.7 h60
  text "UL APPROVED MANUFACTURED SOURCE FOR FR4." at 409.7,-1348.7 h60
  text "3.  SOLDER PLATE WILL BE RoHS COMPLIANT." at 109.7,-1548.7 h60
  text "4.  SOLDER MASK LPI (LIQUID PHOTO IMAGEABLE) BOTH SIDES. COLOR GREEN." at 109.7,-1748.7 h60
  text "SOLDER MASK (REGISTRATION) -0/+0.003\"" at 409.7,-1948.7 h60
  text "5.  SILKSCREEN TOP/BOTTOM SIDE. COLOR WHITE.(MIN.WIDTH 0.005\" MAX.WIDTH 0.010\")" at 109.7,-2148.7 h60
  text "6.  FINISH TO BE SMOBC." at 109.7,-2348.7 h60
  text "7.  LEAD FREE HASL (HOT AIR SOLDER LEVEL) OR RoHS COMPLIANT." at 109.7,-2548.7 h60
  text "8.  BOARD DIMENTION +/- 0.005\"" at 109.7,-2748.7 h60
  text "9.  DRILL TOLERANCE+/-0.003\"" at 109.7,-2948.7 h60
  text "10.  TRACE WIDTH UNDER 0.010\" +/- 0.002\"" at 109.7,-3148.7 h60
  text "TRACE WIDTH OVER 0.011\" +/- 0.005\"" at 509.7,-3348.7 h60
  text "11.  TRACE SPACE +/- 0.003\"" at 109.7,-3548.7 h60
  text "12.  SLOTS WIDTH & LENGHTH +/- 0.005\"" at 109.7,-3748.7 h60
  text "13.  MATERIAL FR4 COPPER 2oz THICKNESS 0.040\"" at 101,-3974 h60
  text "14.  FAB HOUSE LOGO,DATE CODE TO BE IN SILK SCREEN ONLY.DO NOT USE COPPER." at 100,-4194 h60
DRAWING_ORIGIN:
  lines w1: -25,0 25,0 ; 0,-25 0,25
